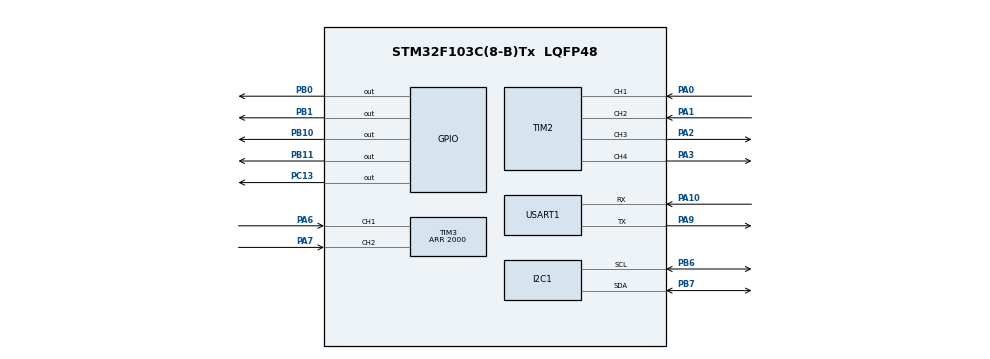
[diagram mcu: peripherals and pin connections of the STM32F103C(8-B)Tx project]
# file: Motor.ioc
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Mcu.Family=STM32F1
Mcu.Name=STM32F103C(8-B)Tx
Mcu.Package=LQFP48
NVIC.PriorityGroup=NVIC_PRIORITYGROUP_4
PA0-WKUP.GPIO_PuPd=GPIO_PULLUP
PA0-WKUP.Signal=S_TIM2_CH1_ETR
PA1.GPIO_PuPd=GPIO_PULLUP
PA1.Signal=S_TIM2_CH2
PA10.Mode=Asynchronous
PA10.Signal=USART1_RX
PA13.Mode=Serial_Wire
PA13.Signal=SYS_JTMS-SWDIO
PA14.Mode=Serial_Wire
PA14.Signal=SYS_JTCK-SWCLK
PA2.Signal=S_TIM2_CH3
PA3.Signal=S_TIM2_CH4
PA6.GPIO_PuPd=GPIO_PULLUP
PA6.Signal=S_TIM3_CH1
PA7.GPIO_PuPd=GPIO_PULLUP
PA7.Signal=S_TIM3_CH2
PA9.Mode=Asynchronous
PA9.Signal=USART1_TX
PB0.Signal=GPIO_Output
PB1.Signal=GPIO_Output
PB10.Signal=GPIO_Output
PB11.Signal=GPIO_Output
PB6.Mode=I2C
PB6.Signal=I2C1_SCL
PB7.Mode=I2C
PB7.Signal=I2C1_SDA
PC13-TAMPER-RTC.Signal=GPIO_Output
PD0-OSC_IN.Mode=HSE-External-Oscillator
PD0-OSC_IN.Signal=RCC_OSC_IN
PD1-OSC_OUT.Mode=HSE-External-Oscillator
PD1-OSC_OUT.Signal=RCC_OSC_OUT
ProjectManager.HeapSize=0x200
ProjectManager.StackSize=0x400
ProjectManager.TargetToolchain=STM32CubeIDE
RCC.AHBFreq_Value=8000000
RCC.APB1CLKDivider=RCC_HCLK_DIV2
RCC.APB1Freq_Value=4000000
RCC.APB1TimFreq_Value=8000000
RCC.APB2Freq_Value=8000000
RCC.APB2TimFreq_Value=8000000
RCC.HCLKFreq_Value=8000000
RCC.PLLMUL=RCC_PLL_MUL9
RCC.PLLSourceVirtual=RCC_PLLSOURCE_HSE
RCC.SYSCLKFreq_VALUE=8000000
RCC.SYSCLKSource=RCC_SYSCLKSOURCE_HSE
RCC.USBFreq_Value=72000000
SH.S_TIM2_CH1_ETR.0=TIM2_CH1,Encoder_Interface
SH.S_TIM2_CH2.0=TIM2_CH2,Encoder_Interface
SH.S_TIM2_CH3.0=TIM2_CH3,PWM Generation3 CH3
SH.S_TIM2_CH4.0=TIM2_CH4,PWM Generation4 CH4
SH.S_TIM3_CH1.0=TIM3_CH1,Encoder_Interface
SH.S_TIM3_CH2.0=TIM3_CH2,Encoder_Interface
TIM2.Channel-PWM\ Generation3\ CH3=TIM_CHANNEL_3
TIM2.Channel-PWM\ Generation4\ CH4=TIM_CHANNEL_4
TIM3.Period=2000
USART1.VirtualMode=VM_ASYNC
board=custom

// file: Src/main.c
/* USER CODE BEGIN Header */
/**
  ******************************************************************************
  * @file           : main.c
  * @brief          : Main program body
  ******************************************************************************
  * @attention
  *
  * <h2><center>&copy; Copyright (c) 2019 STMicroelectronics.
  * All rights reserved.</center></h2>
  *
  * This software component is licensed by ST under BSD 3-Clause license,
  * the "License"; You may not use this file except in compliance with the
  * License. You may obtain a copy of the License at:
  *                        opensource.org/licenses/BSD-3-Clause
  *
  ******************************************************************************
  */
/* USER CODE END Header */

#include "main.h"
#include "mpu6050.h"

I2C_HandleTypeDef hi2c1;

TIM_HandleTypeDef htim2;
TIM_HandleTypeDef htim3;

UART_HandleTypeDef huart1;

void SystemClock_Config(void);
static void MX_GPIO_Init(void);
static void MX_TIM2_Init(void);
static void MX_USART1_UART_Init(void);
static void MX_TIM3_Init(void);
static void MX_I2C1_Init(void);

/* USER CODE BEGIN 0 */
#ifdef __GNUC__
  /* With GCC/RAISONANCE, small printf (option LD Linker->Libraries->Small printf
     set to 'Yes') calls __io_putchar() */
  #define PUTCHAR_PROTOTYPE int __io_putchar(int ch)
#else
  #define PUTCHAR_PROTOTYPE int fputc(int ch, FILE *f)
  #define GETCHAR_PROTOTYPE int fgetc(FILE *f)
#endif /* __GNUC__ */
	PUTCHAR_PROTOTYPE
{
  /* Place your implementation of fputc here */
  /* e.g. write a character to the USART */
	HAL_UART_Transmit(&huart1, (uint8_t*)&ch,1,100);

  /* Loop until the end of transmission */

  return ch;
}
/* USER CODE END 0 */

int main(void)
{

  /* MCU Configuration--------------------------------------------------------*/

  /* Reset of all peripherals, Initializes the Flash interface and the Systick. */
  HAL_Init();

  /* Configure the system clock */
  SystemClock_Config();

  /* Initialize all configured peripherals */
  MX_GPIO_Init();
  MX_TIM2_Init();
  MX_USART1_UART_Init();
  MX_TIM3_Init();
  MX_I2C1_Init();

  /* Infinite loop */
  /* USER CODE BEGIN WHILE */
  int i,j = 0;
  HAL_TIM_Encoder_Start(&htim3,TIM_CHANNEL_1);
  HAL_TIM_Encoder_Start(&htim2,TIM_CHANNEL_1);
  HAL_TIM_PWM_Start(&htim2, TIM_CHANNEL_3);
  while (1)
  {
    /* USER CODE END WHILE */
    i = TIM3 -> CNT;
    j = TIM2 -> CNT;
    /* USER CODE BEGIN 3 */
	  printf("Gia tri encoder la %d %d \n",i,j);
  }
  /* USER CODE END 3 */
}

void SystemClock_Config(void)
{
  RCC_OscInitTypeDef RCC_OscInitStruct = {0};
  RCC_ClkInitTypeDef RCC_ClkInitStruct = {0};

  /** Initializes the CPU, AHB and APB busses clocks
  */
  RCC_OscInitStruct.OscillatorType = RCC_OSCILLATORTYPE_HSE;
  RCC_OscInitStruct.HSEState = RCC_HSE_ON;
  RCC_OscInitStruct.HSEPredivValue = RCC_HSE_PREDIV_DIV1;
  RCC_OscInitStruct.HSIState = RCC_HSI_ON;
  RCC_OscInitStruct.PLL.PLLState = RCC_PLL_ON;
  RCC_OscInitStruct.PLL.PLLSource = RCC_PLLSOURCE_HSE;
  RCC_OscInitStruct.PLL.PLLMUL = RCC_PLL_MUL9;
  if (HAL_RCC_OscConfig(&RCC_OscInitStruct) != HAL_OK)
  {
    Error_Handler();
  }
  /** Initializes the CPU, AHB and APB busses clocks
  */
  RCC_ClkInitStruct.ClockType = RCC_CLOCKTYPE_HCLK|RCC_CLOCKTYPE_SYSCLK
                              |RCC_CLOCKTYPE_PCLK1|RCC_CLOCKTYPE_PCLK2;
  RCC_ClkInitStruct.SYSCLKSource = RCC_SYSCLKSOURCE_PLLCLK;
  RCC_ClkInitStruct.AHBCLKDivider = RCC_SYSCLK_DIV1;
  RCC_ClkInitStruct.APB1CLKDivider = RCC_HCLK_DIV2;
  RCC_ClkInitStruct.APB2CLKDivider = RCC_HCLK_DIV1;

  if (HAL_RCC_ClockConfig(&RCC_ClkInitStruct, FLASH_LATENCY_2) != HAL_OK)
  {
    Error_Handler();
  }
}

static void MX_I2C1_Init(void)
{

  hi2c1.Instance = I2C1;
  hi2c1.Init.ClockSpeed = 100000;
  hi2c1.Init.DutyCycle = I2C_DUTYCYCLE_2;
  hi2c1.Init.OwnAddress1 = 0;
  hi2c1.Init.AddressingMode = I2C_ADDRESSINGMODE_7BIT;
  hi2c1.Init.DualAddressMode = I2C_DUALADDRESS_DISABLE;
  hi2c1.Init.OwnAddress2 = 0;
  hi2c1.Init.GeneralCallMode = I2C_GENERALCALL_DISABLE;
  hi2c1.Init.NoStretchMode = I2C_NOSTRETCH_DISABLE;
  if (HAL_I2C_Init(&hi2c1) != HAL_OK)
  {
    Error_Handler();
  }

}

static void MX_TIM2_Init(void)
{

  TIM_Encoder_InitTypeDef sConfig = {0};
  TIM_MasterConfigTypeDef sMasterConfig = {0};
  TIM_OC_InitTypeDef sConfigOC = {0};

  htim2.Instance = TIM2;
  htim2.Init.Prescaler = 0;
  htim2.Init.CounterMode = TIM_COUNTERMODE_UP;
  htim2.Init.Period = 3599;
  htim2.Init.ClockDivision = TIM_CLOCKDIVISION_DIV1;
  htim2.Init.AutoReloadPreload = TIM_AUTORELOAD_PRELOAD_DISABLE;
  if (HAL_TIM_PWM_Init(&htim2) != HAL_OK)
  {
    Error_Handler();
  }
  sConfig.EncoderMode = TIM_ENCODERMODE_TI1;
  sConfig.IC1Polarity = TIM_ICPOLARITY_RISING;
  sConfig.IC1Selection = TIM_ICSELECTION_DIRECTTI;
  sConfig.IC1Prescaler = TIM_ICPSC_DIV1;
  sConfig.IC1Filter = 0;
  sConfig.IC2Polarity = TIM_ICPOLARITY_RISING;
  sConfig.IC2Selection = TIM_ICSELECTION_DIRECTTI;
  sConfig.IC2Prescaler = TIM_ICPSC_DIV1;
  sConfig.IC2Filter = 0;
  if (HAL_TIM_Encoder_Init(&htim2, &sConfig) != HAL_OK)
  {
    Error_Handler();
  }
  sMasterConfig.MasterOutputTrigger = TIM_TRGO_RESET;
  sMasterConfig.MasterSlaveMode = TIM_MASTERSLAVEMODE_DISABLE;
  if (HAL_TIMEx_MasterConfigSynchronization(&htim2, &sMasterConfig) != HAL_OK)
  {
    Error_Handler();
  }
  sConfigOC.OCMode = TIM_OCMODE_PWM1;
  sConfigOC.Pulse = 0;
  sConfigOC.OCPolarity = TIM_OCPOLARITY_HIGH;
  sConfigOC.OCFastMode = TIM_OCFAST_DISABLE;
  if (HAL_TIM_PWM_ConfigChannel(&htim2, &sConfigOC, TIM_CHANNEL_3) != HAL_OK)
  {
    Error_Handler();
  }
  if (HAL_TIM_PWM_ConfigChannel(&htim2, &sConfigOC, TIM_CHANNEL_4) != HAL_OK)
  {
    Error_Handler();
  }
  HAL_TIM_MspPostInit(&htim2);

}

static void MX_TIM3_Init(void)
{

  TIM_Encoder_InitTypeDef sConfig = {0};
  TIM_MasterConfigTypeDef sMasterConfig = {0};

  htim3.Instance = TIM3;
  htim3.Init.Prescaler = 0;
  htim3.Init.CounterMode = TIM_COUNTERMODE_UP;
  htim3.Init.Period = 2000;
  htim3.Init.ClockDivision = TIM_CLOCKDIVISION_DIV1;
  htim3.Init.AutoReloadPreload = TIM_AUTORELOAD_PRELOAD_DISABLE;
  sConfig.EncoderMode = TIM_ENCODERMODE_TI1;
  sConfig.IC1Polarity = TIM_ICPOLARITY_RISING;
  sConfig.IC1Selection = TIM_ICSELECTION_DIRECTTI;
  sConfig.IC1Prescaler = TIM_ICPSC_DIV1;
  sConfig.IC1Filter = 0;
  sConfig.IC2Polarity = TIM_ICPOLARITY_RISING;
  sConfig.IC2Selection = TIM_ICSELECTION_DIRECTTI;
  sConfig.IC2Prescaler = TIM_ICPSC_DIV1;
  sConfig.IC2Filter = 0;
  if (HAL_TIM_Encoder_Init(&htim3, &sConfig) != HAL_OK)
  {
    Error_Handler();
  }
  sMasterConfig.MasterOutputTrigger = TIM_TRGO_RESET;
  sMasterConfig.MasterSlaveMode = TIM_MASTERSLAVEMODE_DISABLE;
  if (HAL_TIMEx_MasterConfigSynchronization(&htim3, &sMasterConfig) != HAL_OK)
  {
    Error_Handler();
  }

}

static void MX_USART1_UART_Init(void)
{

  huart1.Instance = USART1;
  huart1.Init.BaudRate = 115200;
  huart1.Init.WordLength = UART_WORDLENGTH_8B;
  huart1.Init.StopBits = UART_STOPBITS_1;
  huart1.Init.Parity = UART_PARITY_NONE;
  huart1.Init.Mode = UART_MODE_TX_RX;
  huart1.Init.HwFlowCtl = UART_HWCONTROL_NONE;
  huart1.Init.OverSampling = UART_OVERSAMPLING_16;
  if (HAL_UART_Init(&huart1) != HAL_OK)
  {
    Error_Handler();
  }

}

static void MX_GPIO_Init(void)
{
  GPIO_InitTypeDef GPIO_InitStruct = {0};

  /* GPIO Ports Clock Enable */
  __HAL_RCC_GPIOD_CLK_ENABLE();
  __HAL_RCC_GPIOA_CLK_ENABLE();
  __HAL_RCC_GPIOB_CLK_ENABLE();

  /*Configure GPIO pin Output Level */
  HAL_GPIO_WritePin(GPIOB, GPIO_PIN_0|GPIO_PIN_1|GPIO_PIN_10|GPIO_PIN_11, GPIO_PIN_RESET);

  /*Configure GPIO pins : PB0 PB1 PB10 PB11 */
  GPIO_InitStruct.Pin = GPIO_PIN_0|GPIO_PIN_1|GPIO_PIN_10|GPIO_PIN_11;
  GPIO_InitStruct.Mode = GPIO_MODE_OUTPUT_PP;
  GPIO_InitStruct.Pull = GPIO_NOPULL;
  GPIO_InitStruct.Speed = GPIO_SPEED_FREQ_LOW;
  HAL_GPIO_Init(GPIOB, &GPIO_InitStruct);

}

void Error_Handler(void)
{
}

/************************ (C) COPYRIGHT STMicroelectronics *****END OF FILE****/
